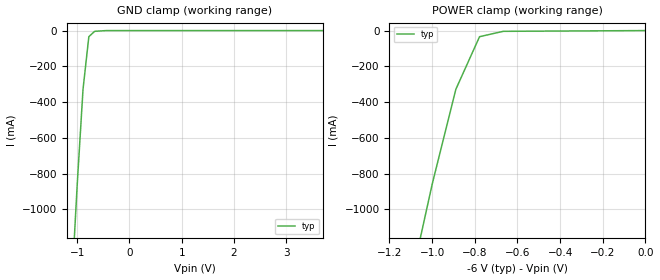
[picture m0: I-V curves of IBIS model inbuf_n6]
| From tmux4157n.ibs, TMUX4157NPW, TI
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| inbuf_n6
[Model]   inbuf_n6
Model_type   Input
Vinl = 0.8
Vinh = 1.35
|   typ   min   max
C_comp   6.976543e-12   NA   NA
[Voltage Range]   -6   NA   NA
[Temperature Range]   27   NA   NA
[Power Clamp Reference]   -6   NA   NA
[GND Clamp Reference]   0   NA   NA
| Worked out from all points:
|   GND clamp passes 1 mA (typ) near -0.57 V on its own axis
|   POWER clamp passes 1 mA (typ) near -0.57 V on its own axis
[GND Clamp]
|   Voltage   I(typ)   I(min)   I(max)
-6V       -22.68A    NA         NA
-1.111V   -1.46A     NA         NA
-1V       -859.5mA   NA         NA
-888.9mV  -327.8mA   NA         NA
-777.8mV  -34.15mA   NA         NA
-666.7mV  -4.149mA   NA         NA
-444.4mV  -26.07uA   NA         NA
5V        2.068uA    NA         NA
[POWER Clamp]
|   Voltage   I(typ)   I(min)   I(max)
-11V      -41.81A    NA         NA
-1.111V   -1.46A     NA         NA
-1V       -859.5mA   NA         NA
-888.9mV  -328.2mA   NA         NA
-777.8mV  -34.15mA   NA         NA
-666.7mV  -4.149mA   NA         NA
0V        128.4pA    NA         NA
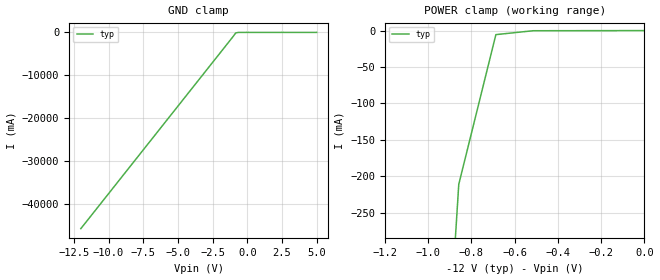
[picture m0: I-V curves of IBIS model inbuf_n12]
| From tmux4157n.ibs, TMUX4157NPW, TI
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| inbuf_n12
[Model]   inbuf_n12
Model_type   Input
Vinl = 0.8
Vinh = 1.35
|   typ   min   max
C_comp   1.008417e-11   NA   NA
[Voltage Range]   -12   NA   NA
[Temperature Range]   27   NA   NA
[Power Clamp Reference]   -12   NA   NA
[GND Clamp Reference]   0   NA   NA
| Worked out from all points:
|   GND clamp passes 1 mA (typ) near -0.53 V on its own axis
|   POWER clamp passes 1 mA (typ) near -0.54 V on its own axis
[GND Clamp]
|   Voltage   I(typ)   I(min)   I(max)
-12V      -45.63A    NA         NA
-1.01V    -912.3mA   NA         NA
-838.4mV  -145.9mA   NA         NA
-666.7mV  -4.149mA   NA         NA
-494.9mV  -125.7uA   NA         NA
5V        2.458uA    NA         NA
[POWER Clamp]
|   Voltage   I(typ)   I(min)   I(max)
-17V      -64.71A    NA         NA
-1.03V    -1.019A    NA         NA
-858.6mV  -211.2mA   NA         NA
-686.9mV  -5.554mA   NA         NA
-515.2mV  -222.6uA   NA         NA
0V        228.6pA    NA         NA
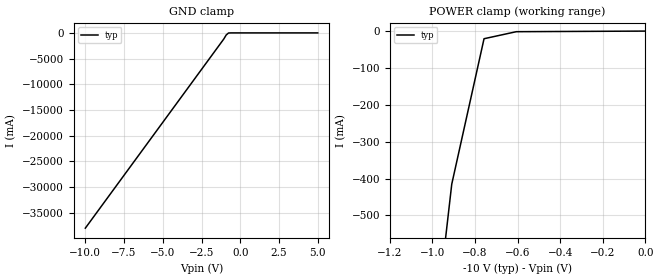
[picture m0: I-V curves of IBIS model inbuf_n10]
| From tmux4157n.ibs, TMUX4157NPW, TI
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| inbuf_n10
[Model]   inbuf_n10
Model_type   Input
Vinl = 0.8
Vinh = 1.35
|   typ   min   max
C_comp   1.008417e-11   NA   NA
[Voltage Range]   -10   NA   NA
[Temperature Range]   27   NA   NA
[Power Clamp Reference]   -10   NA   NA
[GND Clamp Reference]   0   NA   NA
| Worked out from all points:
|   GND clamp passes 1 mA (typ) near -0.55 V on its own axis
|   POWER clamp passes 1 mA (typ) near -0.55 V on its own axis
[GND Clamp]
|   Voltage   I(typ)   I(min)   I(max)
-10V      -37.99A    NA         NA
-1.061V   -1.182A    NA         NA
-909.1mV  -414.9mA   NA         NA
-757.6mV  -20.72mA   NA         NA
-606.1mV  -1.647mA   NA         NA
5V        2.356uA    NA         NA
[POWER Clamp]
|   Voltage   I(typ)   I(min)   I(max)
-15V      -57.08A    NA         NA
-1.061V   -1.182A    NA         NA
-909.1mV  -415.1mA   NA         NA
-757.6mV  -20.72mA   NA         NA
-606.1mV  -1.647mA   NA         NA
0V        195.2pA    NA         NA
